# Generated by FakeRAM 2.0
VERSION 5.7 ;
BUSBITCHARS "[]" ;
PROPERTYDEFINITIONS
  MACRO width INTEGER ;
  MACRO depth INTEGER ;
  MACRO banks INTEGER ;
END PROPERTYDEFINITIONS
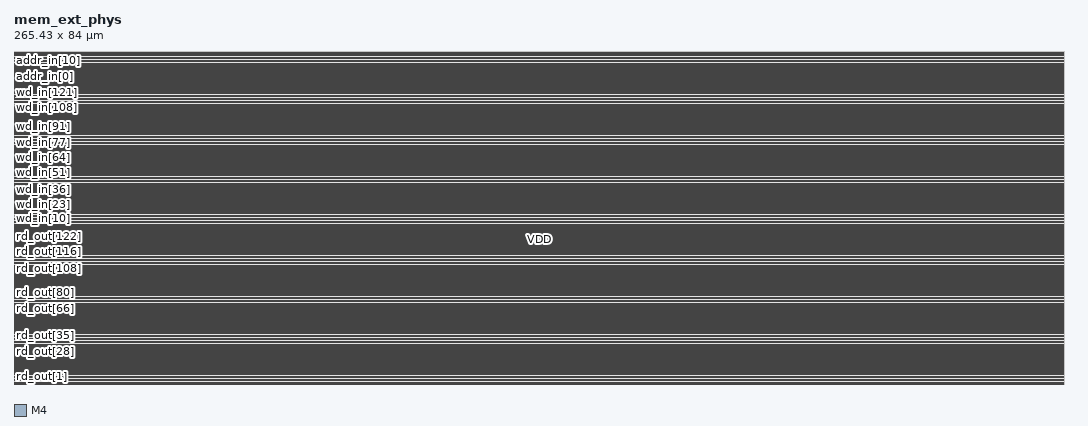
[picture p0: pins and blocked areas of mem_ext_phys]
MACRO mem_ext_phys
  PROPERTY width 128 ;
  PROPERTY depth 4096 ;
  PROPERTY banks 1 ;
  FOREIGN mem_ext 0 0 ;
  SYMMETRY X Y R90 ;
  SIZE 265.4300 BY 84.0000 ;
  CLASS BLOCK ;
  PIN rd_out[0]
    DIRECTION OUTPUT ;
    USE SIGNAL ;
    PORT
      LAYER M4 ;
      RECT 0.00000 0.04800 0.02400 0.07200 ;
    END
  END rd_out[0]
  PIN rd_out[1]
    DIRECTION OUTPUT ;
    USE SIGNAL ;
    PORT
      LAYER M4 ;
      RECT 0.00000 0.33600 0.02400 0.36000 ;
    END
  END rd_out[1]
  PIN rd_out[2]
    DIRECTION OUTPUT ;
    USE SIGNAL ;
    PORT
      LAYER M4 ;
      RECT 0.00000 0.62400 0.02400 0.64800 ;
    END
  END rd_out[2]
  PIN rd_out[3]
    DIRECTION OUTPUT ;
    USE SIGNAL ;
    PORT
      LAYER M4 ;
      RECT 0.00000 0.91200 0.02400 0.93600 ;
    END
  END rd_out[3]
  PIN rd_out[4]
    DIRECTION OUTPUT ;
    USE SIGNAL ;
    PORT
      LAYER M4 ;
      RECT 0.00000 1.20000 0.02400 1.22400 ;
    END
  END rd_out[4]
  PIN rd_out[5]
    DIRECTION OUTPUT ;
    USE SIGNAL ;
    PORT
      LAYER M4 ;
      RECT 0.00000 1.48800 0.02400 1.51200 ;
    END
  END rd_out[5]
  PIN rd_out[6]
    DIRECTION OUTPUT ;
    USE SIGNAL ;
    PORT
      LAYER M4 ;
      RECT 0.00000 1.77600 0.02400 1.80000 ;
    END
  END rd_out[6]
  PIN rd_out[7]
    DIRECTION OUTPUT ;
    USE SIGNAL ;
    PORT
      LAYER M4 ;
      RECT 0.00000 2.06400 0.02400 2.08800 ;
    END
  END rd_out[7]
  PIN rd_out[8]
    DIRECTION OUTPUT ;
    USE SIGNAL ;
    PORT
      LAYER M4 ;
      RECT 0.00000 2.35200 0.02400 2.37600 ;
    END
  END rd_out[8]
  PIN rd_out[9]
    DIRECTION OUTPUT ;
    USE SIGNAL ;
    PORT
      LAYER M4 ;
      RECT 0.00000 2.64000 0.02400 2.66400 ;
    END
  END rd_out[9]
  PIN rd_out[10]
    DIRECTION OUTPUT ;
    USE SIGNAL ;
    PORT
      LAYER M4 ;
      RECT 0.00000 2.92800 0.02400 2.95200 ;
    END
  END rd_out[10]
  PIN rd_out[11]
    DIRECTION OUTPUT ;
    USE SIGNAL ;
    PORT
      LAYER M4 ;
      RECT 0.00000 3.21600 0.02400 3.24000 ;
    END
  END rd_out[11]
  PIN rd_out[12]
    DIRECTION OUTPUT ;
    USE SIGNAL ;
    PORT
      LAYER M4 ;
      RECT 0.00000 3.50400 0.02400 3.52800 ;
    END
  END rd_out[12]
  PIN rd_out[13]
    DIRECTION OUTPUT ;
    USE SIGNAL ;
    PORT
      LAYER M4 ;
      RECT 0.00000 3.79200 0.02400 3.81600 ;
    END
  END rd_out[13]
  PIN rd_out[14]
    DIRECTION OUTPUT ;
    USE SIGNAL ;
    PORT
      LAYER M4 ;
      RECT 0.00000 4.08000 0.02400 4.10400 ;
    END
  END rd_out[14]
  PIN rd_out[15]
    DIRECTION OUTPUT ;
    USE SIGNAL ;
    PORT
      LAYER M4 ;
      RECT 0.00000 4.36800 0.02400 4.39200 ;
    END
  END rd_out[15]
  PIN rd_out[16]
    DIRECTION OUTPUT ;
    USE SIGNAL ;
    PORT
      LAYER M4 ;
      RECT 0.00000 4.65600 0.02400 4.68000 ;
    END
  END rd_out[16]
  PIN rd_out[17]
    DIRECTION OUTPUT ;
    USE SIGNAL ;
    PORT
      LAYER M4 ;
      RECT 0.00000 4.94400 0.02400 4.96800 ;
    END
  END rd_out[17]
  PIN rd_out[18]
    DIRECTION OUTPUT ;
    USE SIGNAL ;
    PORT
      LAYER M4 ;
      RECT 0.00000 5.23200 0.02400 5.25600 ;
    END
  END rd_out[18]
  PIN rd_out[19]
    DIRECTION OUTPUT ;
    USE SIGNAL ;
    PORT
      LAYER M4 ;
      RECT 0.00000 5.52000 0.02400 5.54400 ;
    END
  END rd_out[19]
  PIN rd_out[20]
    DIRECTION OUTPUT ;
    USE SIGNAL ;
    PORT
      LAYER M4 ;
      RECT 0.00000 5.80800 0.02400 5.83200 ;
    END
  END rd_out[20]
  PIN rd_out[21]
    DIRECTION OUTPUT ;
    USE SIGNAL ;
    PORT
      LAYER M4 ;
      RECT 0.00000 6.09600 0.02400 6.12000 ;
    END
  END rd_out[21]
  PIN rd_out[22]
    DIRECTION OUTPUT ;
    USE SIGNAL ;
    PORT
      LAYER M4 ;
      RECT 0.00000 6.38400 0.02400 6.40800 ;
    END
  END rd_out[22]
  PIN rd_out[23]
    DIRECTION OUTPUT ;
    USE SIGNAL ;
    PORT
      LAYER M4 ;
      RECT 0.00000 6.67200 0.02400 6.69600 ;
    END
  END rd_out[23]
  PIN rd_out[24]
    DIRECTION OUTPUT ;
    USE SIGNAL ;
    PORT
      LAYER M4 ;
      RECT 0.00000 6.96000 0.02400 6.98400 ;
    END
  END rd_out[24]
  PIN rd_out[25]
    DIRECTION OUTPUT ;
    USE SIGNAL ;
    PORT
      LAYER M4 ;
      RECT 0.00000 7.24800 0.02400 7.27200 ;
    END
  END rd_out[25]
  PIN rd_out[26]
    DIRECTION OUTPUT ;
    USE SIGNAL ;
    PORT
      LAYER M4 ;
      RECT 0.00000 7.53600 0.02400 7.56000 ;
    END
  END rd_out[26]
  PIN rd_out[27]
    DIRECTION OUTPUT ;
    USE SIGNAL ;
    PORT
      LAYER M4 ;
      RECT 0.00000 7.82400 0.02400 7.84800 ;
    END
  END rd_out[27]
  PIN rd_out[28]
    DIRECTION OUTPUT ;
    USE SIGNAL ;
    PORT
      LAYER M4 ;
      RECT 0.00000 8.11200 0.02400 8.13600 ;
    END
  END rd_out[28]
  PIN rd_out[29]
    DIRECTION OUTPUT ;
    USE SIGNAL ;
    PORT
      LAYER M4 ;
      RECT 0.00000 8.40000 0.02400 8.42400 ;
    END
  END rd_out[29]
  PIN rd_out[30]
    DIRECTION OUTPUT ;
    USE SIGNAL ;
    PORT
      LAYER M4 ;
      RECT 0.00000 8.68800 0.02400 8.71200 ;
    END
  END rd_out[30]
  PIN rd_out[31]
    DIRECTION OUTPUT ;
    USE SIGNAL ;
    PORT
      LAYER M4 ;
      RECT 0.00000 8.97600 0.02400 9.00000 ;
    END
  END rd_out[31]
  PIN rd_out[32]
    DIRECTION OUTPUT ;
    USE SIGNAL ;
    PORT
      LAYER M4 ;
      RECT 0.00000 9.26400 0.02400 9.28800 ;
    END
  END rd_out[32]
  PIN rd_out[33]
    DIRECTION OUTPUT ;
    USE SIGNAL ;
    PORT
      LAYER M4 ;
      RECT 0.00000 9.55200 0.02400 9.57600 ;
    END
  END rd_out[33]
  PIN rd_out[34]
    DIRECTION OUTPUT ;
    USE SIGNAL ;
    PORT
      LAYER M4 ;
      RECT 0.00000 9.84000 0.02400 9.86400 ;
    END
  END rd_out[34]
  PIN rd_out[35]
    DIRECTION OUTPUT ;
    USE SIGNAL ;
    PORT
      LAYER M4 ;
      RECT 0.00000 10.12800 0.02400 10.15200 ;
    END
  END rd_out[35]
  PIN rd_out[36]
    DIRECTION OUTPUT ;
    USE SIGNAL ;
    PORT
      LAYER M4 ;
      RECT 0.00000 10.41600 0.02400 10.44000 ;
    END
  END rd_out[36]
  PIN rd_out[37]
    DIRECTION OUTPUT ;
    USE SIGNAL ;
    PORT
      LAYER M4 ;
      RECT 0.00000 10.70400 0.02400 10.72800 ;
    END
  END rd_out[37]
  PIN rd_out[38]
    DIRECTION OUTPUT ;
    USE SIGNAL ;
    PORT
      LAYER M4 ;
      RECT 0.00000 10.99200 0.02400 11.01600 ;
    END
  END rd_out[38]
  PIN rd_out[39]
    DIRECTION OUTPUT ;
    USE SIGNAL ;
    PORT
      LAYER M4 ;
      RECT 0.00000 11.28000 0.02400 11.30400 ;
    END
  END rd_out[39]
  PIN rd_out[40]
    DIRECTION OUTPUT ;
    USE SIGNAL ;
    PORT
      LAYER M4 ;
      RECT 0.00000 11.56800 0.02400 11.59200 ;
    END
  END rd_out[40]
  PIN rd_out[41]
    DIRECTION OUTPUT ;
    USE SIGNAL ;
    PORT
      LAYER M4 ;
      RECT 0.00000 11.85600 0.02400 11.88000 ;
    END
  END rd_out[41]
  PIN rd_out[42]
    DIRECTION OUTPUT ;
    USE SIGNAL ;
    PORT
      LAYER M4 ;
      RECT 0.00000 12.14400 0.02400 12.16800 ;
    END
  END rd_out[42]
  PIN rd_out[43]
    DIRECTION OUTPUT ;
    USE SIGNAL ;
    PORT
      LAYER M4 ;
      RECT 0.00000 12.43200 0.02400 12.45600 ;
    END
  END rd_out[43]
  PIN rd_out[44]
    DIRECTION OUTPUT ;
    USE SIGNAL ;
    PORT
      LAYER M4 ;
      RECT 0.00000 12.72000 0.02400 12.74400 ;
    END
  END rd_out[44]
  PIN rd_out[45]
    DIRECTION OUTPUT ;
    USE SIGNAL ;
    PORT
      LAYER M4 ;
      RECT 0.00000 13.00800 0.02400 13.03200 ;
    END
  END rd_out[45]
  PIN rd_out[46]
    DIRECTION OUTPUT ;
    USE SIGNAL ;
    PORT
      LAYER M4 ;
      RECT 0.00000 13.29600 0.02400 13.32000 ;
    END
  END rd_out[46]
  PIN rd_out[47]
    DIRECTION OUTPUT ;
    USE SIGNAL ;
    PORT
      LAYER M4 ;
      RECT 0.00000 13.58400 0.02400 13.60800 ;
    END
  END rd_out[47]
  PIN rd_out[48]
    DIRECTION OUTPUT ;
    USE SIGNAL ;
    PORT
      LAYER M4 ;
      RECT 0.00000 13.87200 0.02400 13.89600 ;
    END
  END rd_out[48]
  PIN rd_out[49]
    DIRECTION OUTPUT ;
    USE SIGNAL ;
    PORT
      LAYER M4 ;
      RECT 0.00000 14.16000 0.02400 14.18400 ;
    END
  END rd_out[49]
  PIN rd_out[50]
    DIRECTION OUTPUT ;
    USE SIGNAL ;
    PORT
      LAYER M4 ;
      RECT 0.00000 14.44800 0.02400 14.47200 ;
    END
  END rd_out[50]
  PIN rd_out[51]
    DIRECTION OUTPUT ;
    USE SIGNAL ;
    PORT
      LAYER M4 ;
      RECT 0.00000 14.73600 0.02400 14.76000 ;
    END
  END rd_out[51]
  PIN rd_out[52]
    DIRECTION OUTPUT ;
    USE SIGNAL ;
    PORT
      LAYER M4 ;
      RECT 0.00000 15.02400 0.02400 15.04800 ;
    END
  END rd_out[52]
  PIN rd_out[53]
    DIRECTION OUTPUT ;
    USE SIGNAL ;
    PORT
      LAYER M4 ;
      RECT 0.00000 15.31200 0.02400 15.33600 ;
    END
  END rd_out[53]
  PIN rd_out[54]
    DIRECTION OUTPUT ;
    USE SIGNAL ;
    PORT
      LAYER M4 ;
      RECT 0.00000 15.60000 0.02400 15.62400 ;
    END
  END rd_out[54]
  PIN rd_out[55]
    DIRECTION OUTPUT ;
    USE SIGNAL ;
    PORT
      LAYER M4 ;
      RECT 0.00000 15.88800 0.02400 15.91200 ;
    END
  END rd_out[55]
  PIN rd_out[56]
    DIRECTION OUTPUT ;
    USE SIGNAL ;
    PORT
      LAYER M4 ;
      RECT 0.00000 16.17600 0.02400 16.20000 ;
    END
  END rd_out[56]
  PIN rd_out[57]
    DIRECTION OUTPUT ;
    USE SIGNAL ;
    PORT
      LAYER M4 ;
      RECT 0.00000 16.46400 0.02400 16.48800 ;
    END
  END rd_out[57]
  PIN rd_out[58]
    DIRECTION OUTPUT ;
    USE SIGNAL ;
    PORT
      LAYER M4 ;
      RECT 0.00000 16.75200 0.02400 16.77600 ;
    END
  END rd_out[58]
  PIN rd_out[59]
    DIRECTION OUTPUT ;
    USE SIGNAL ;
    PORT
      LAYER M4 ;
      RECT 0.00000 17.04000 0.02400 17.06400 ;
    END
  END rd_out[59]
  PIN rd_out[60]
    DIRECTION OUTPUT ;
    USE SIGNAL ;
    PORT
      LAYER M4 ;
      RECT 0.00000 17.32800 0.02400 17.35200 ;
    END
  END rd_out[60]
  PIN rd_out[61]
    DIRECTION OUTPUT ;
    USE SIGNAL ;
    PORT
      LAYER M4 ;
      RECT 0.00000 17.61600 0.02400 17.64000 ;
    END
  END rd_out[61]
  PIN rd_out[62]
    DIRECTION OUTPUT ;
    USE SIGNAL ;
    PORT
      LAYER M4 ;
      RECT 0.00000 17.90400 0.02400 17.92800 ;
    END
  END rd_out[62]
  PIN rd_out[63]
    DIRECTION OUTPUT ;
    USE SIGNAL ;
    PORT
      LAYER M4 ;
      RECT 0.00000 18.19200 0.02400 18.21600 ;
    END
  END rd_out[63]
  PIN rd_out[64]
    DIRECTION OUTPUT ;
    USE SIGNAL ;
    PORT
      LAYER M4 ;
      RECT 0.00000 18.48000 0.02400 18.50400 ;
    END
  END rd_out[64]
  PIN rd_out[65]
    DIRECTION OUTPUT ;
    USE SIGNAL ;
    PORT
      LAYER M4 ;
      RECT 0.00000 18.76800 0.02400 18.79200 ;
    END
  END rd_out[65]
  PIN rd_out[66]
    DIRECTION OUTPUT ;
    USE SIGNAL ;
    PORT
      LAYER M4 ;
      RECT 0.00000 19.05600 0.02400 19.08000 ;
    END
  END rd_out[66]
  PIN rd_out[67]
    DIRECTION OUTPUT ;
    USE SIGNAL ;
    PORT
      LAYER M4 ;
      RECT 0.00000 19.34400 0.02400 19.36800 ;
    END
  END rd_out[67]
  PIN rd_out[68]
    DIRECTION OUTPUT ;
    USE SIGNAL ;
    PORT
      LAYER M4 ;
      RECT 0.00000 19.63200 0.02400 19.65600 ;
    END
  END rd_out[68]
  PIN rd_out[69]
    DIRECTION OUTPUT ;
    USE SIGNAL ;
    PORT
      LAYER M4 ;
      RECT 0.00000 19.92000 0.02400 19.94400 ;
    END
  END rd_out[69]
  PIN rd_out[70]
    DIRECTION OUTPUT ;
    USE SIGNAL ;
    PORT
      LAYER M4 ;
      RECT 0.00000 20.20800 0.02400 20.23200 ;
    END
  END rd_out[70]
  PIN rd_out[71]
    DIRECTION OUTPUT ;
    USE SIGNAL ;
    PORT
      LAYER M4 ;
      RECT 0.00000 20.49600 0.02400 20.52000 ;
    END
  END rd_out[71]
  PIN rd_out[72]
    DIRECTION OUTPUT ;
    USE SIGNAL ;
    PORT
      LAYER M4 ;
      RECT 0.00000 20.78400 0.02400 20.80800 ;
    END
  END rd_out[72]
  PIN rd_out[73]
    DIRECTION OUTPUT ;
    USE SIGNAL ;
    PORT
      LAYER M4 ;
      RECT 0.00000 21.07200 0.02400 21.09600 ;
    END
  END rd_out[73]
  PIN rd_out[74]
    DIRECTION OUTPUT ;
    USE SIGNAL ;
    PORT
      LAYER M4 ;
      RECT 0.00000 21.36000 0.02400 21.38400 ;
    END
  END rd_out[74]
  PIN rd_out[75]
    DIRECTION OUTPUT ;
    USE SIGNAL ;
    PORT
      LAYER M4 ;
      RECT 0.00000 21.64800 0.02400 21.67200 ;
    END
  END rd_out[75]
  PIN rd_out[76]
    DIRECTION OUTPUT ;
    USE SIGNAL ;
    PORT
      LAYER M4 ;
      RECT 0.00000 21.93600 0.02400 21.96000 ;
    END
  END rd_out[76]
  PIN rd_out[77]
    DIRECTION OUTPUT ;
    USE SIGNAL ;
    PORT
      LAYER M4 ;
      RECT 0.00000 22.22400 0.02400 22.24800 ;
    END
  END rd_out[77]
  PIN rd_out[78]
    DIRECTION OUTPUT ;
    USE SIGNAL ;
    PORT
      LAYER M4 ;
      RECT 0.00000 22.51200 0.02400 22.53600 ;
    END
  END rd_out[78]
  PIN rd_out[79]
    DIRECTION OUTPUT ;
    USE SIGNAL ;
    PORT
      LAYER M4 ;
      RECT 0.00000 22.80000 0.02400 22.82400 ;
    END
  END rd_out[79]
  PIN rd_out[80]
    DIRECTION OUTPUT ;
    USE SIGNAL ;
    PORT
      LAYER M4 ;
      RECT 0.00000 23.08800 0.02400 23.11200 ;
    END
  END rd_out[80]
  PIN rd_out[81]
    DIRECTION OUTPUT ;
    USE SIGNAL ;
    PORT
      LAYER M4 ;
      RECT 0.00000 23.37600 0.02400 23.40000 ;
    END
  END rd_out[81]
  PIN rd_out[82]
    DIRECTION OUTPUT ;
    USE SIGNAL ;
    PORT
      LAYER M4 ;
      RECT 0.00000 23.66400 0.02400 23.68800 ;
    END
  END rd_out[82]
  PIN rd_out[83]
    DIRECTION OUTPUT ;
    USE SIGNAL ;
    PORT
      LAYER M4 ;
      RECT 0.00000 23.95200 0.02400 23.97600 ;
    END
  END rd_out[83]
  PIN rd_out[84]
    DIRECTION OUTPUT ;
    USE SIGNAL ;
    PORT
      LAYER M4 ;
      RECT 0.00000 24.24000 0.02400 24.26400 ;
    END
  END rd_out[84]
  PIN rd_out[85]
    DIRECTION OUTPUT ;
    USE SIGNAL ;
    PORT
      LAYER M4 ;
      RECT 0.00000 24.52800 0.02400 24.55200 ;
    END
  END rd_out[85]
  PIN rd_out[86]
    DIRECTION OUTPUT ;
    USE SIGNAL ;
    PORT
      LAYER M4 ;
      RECT 0.00000 24.81600 0.02400 24.84000 ;
    END
  END rd_out[86]
  PIN rd_out[87]
    DIRECTION OUTPUT ;
    USE SIGNAL ;
    PORT
      LAYER M4 ;
      RECT 0.00000 25.10400 0.02400 25.12800 ;
    END
  END rd_out[87]
  PIN rd_out[88]
    DIRECTION OUTPUT ;
    USE SIGNAL ;
    PORT
      LAYER M4 ;
      RECT 0.00000 25.39200 0.02400 25.41600 ;
    END
  END rd_out[88]
  PIN rd_out[89]
    DIRECTION OUTPUT ;
    USE SIGNAL ;
    PORT
      LAYER M4 ;
      RECT 0.00000 25.68000 0.02400 25.70400 ;
    END
  END rd_out[89]
  PIN rd_out[90]
    DIRECTION OUTPUT ;
    USE SIGNAL ;
    PORT
      LAYER M4 ;
      RECT 0.00000 25.96800 0.02400 25.99200 ;
    END
  END rd_out[90]
  PIN rd_out[91]
    DIRECTION OUTPUT ;
    USE SIGNAL ;
    PORT
      LAYER M4 ;
      RECT 0.00000 26.25600 0.02400 26.28000 ;
    END
  END rd_out[91]
  PIN rd_out[92]
    DIRECTION OUTPUT ;
    USE SIGNAL ;
    PORT
      LAYER M4 ;
      RECT 0.00000 26.54400 0.02400 26.56800 ;
    END
  END rd_out[92]
  PIN rd_out[93]
    DIRECTION OUTPUT ;
    USE SIGNAL ;
    PORT
      LAYER M4 ;
      RECT 0.00000 26.83200 0.02400 26.85600 ;
    END
  END rd_out[93]
  PIN rd_out[94]
    DIRECTION OUTPUT ;
    USE SIGNAL ;
    PORT
      LAYER M4 ;
      RECT 0.00000 27.12000 0.02400 27.14400 ;
    END
  END rd_out[94]
  PIN rd_out[95]
    DIRECTION OUTPUT ;
    USE SIGNAL ;
    PORT
      LAYER M4 ;
      RECT 0.00000 27.40800 0.02400 27.43200 ;
    END
  END rd_out[95]
  PIN rd_out[96]
    DIRECTION OUTPUT ;
    USE SIGNAL ;
    PORT
      LAYER M4 ;
      RECT 0.00000 27.69600 0.02400 27.72000 ;
    END
  END rd_out[96]
  PIN rd_out[97]
    DIRECTION OUTPUT ;
    USE SIGNAL ;
    PORT
      LAYER M4 ;
      RECT 0.00000 27.98400 0.02400 28.00800 ;
    END
  END rd_out[97]
  PIN rd_out[98]
    DIRECTION OUTPUT ;
    USE SIGNAL ;
    PORT
      LAYER M4 ;
      RECT 0.00000 28.27200 0.02400 28.29600 ;
    END
  END rd_out[98]
  PIN rd_out[99]
    DIRECTION OUTPUT ;
    USE SIGNAL ;
    PORT
      LAYER M4 ;
      RECT 0.00000 28.56000 0.02400 28.58400 ;
    END
  END rd_out[99]
  PIN rd_out[100]
    DIRECTION OUTPUT ;
    USE SIGNAL ;
    PORT
      LAYER M4 ;
      RECT 0.00000 28.84800 0.02400 28.87200 ;
    END
  END rd_out[100]
  PIN rd_out[101]
    DIRECTION OUTPUT ;
    USE SIGNAL ;
    PORT
      LAYER M4 ;
      RECT 0.00000 29.13600 0.02400 29.16000 ;
    END
  END rd_out[101]
  PIN rd_out[102]
    DIRECTION OUTPUT ;
    USE SIGNAL ;
    PORT
      LAYER M4 ;
      RECT 0.00000 29.42400 0.02400 29.44800 ;
    END
  END rd_out[102]
  PIN rd_out[103]
    DIRECTION OUTPUT ;
    USE SIGNAL ;
    PORT
      LAYER M4 ;
      RECT 0.00000 29.71200 0.02400 29.73600 ;
    END
  END rd_out[103]
  PIN rd_out[104]
    DIRECTION OUTPUT ;
    USE SIGNAL ;
    PORT
      LAYER M4 ;
      RECT 0.00000 30.00000 0.02400 30.02400 ;
    END
  END rd_out[104]
  PIN rd_out[105]
    DIRECTION OUTPUT ;
    USE SIGNAL ;
    PORT
      LAYER M4 ;
      RECT 0.00000 30.28800 0.02400 30.31200 ;
    END
  END rd_out[105]
  PIN rd_out[106]
    DIRECTION OUTPUT ;
    USE SIGNAL ;
    PORT
      LAYER M4 ;
      RECT 0.00000 30.57600 0.02400 30.60000 ;
    END
  END rd_out[106]
  PIN rd_out[107]
    DIRECTION OUTPUT ;
    USE SIGNAL ;
    PORT
      LAYER M4 ;
      RECT 0.00000 30.86400 0.02400 30.88800 ;
    END
  END rd_out[107]
  PIN rd_out[108]
    DIRECTION OUTPUT ;
    USE SIGNAL ;
    PORT
      LAYER M4 ;
      RECT 0.00000 31.15200 0.02400 31.17600 ;
    END
  END rd_out[108]
  PIN rd_out[109]
    DIRECTION OUTPUT ;
    USE SIGNAL ;
    PORT
      LAYER M4 ;
      RECT 0.00000 31.44000 0.02400 31.46400 ;
    END
  END rd_out[109]
  PIN rd_out[110]
    DIRECTION OUTPUT ;
    USE SIGNAL ;
    PORT
      LAYER M4 ;
      RECT 0.00000 31.72800 0.02400 31.75200 ;
    END
  END rd_out[110]
  PIN rd_out[111]
    DIRECTION OUTPUT ;
    USE SIGNAL ;
    PORT
      LAYER M4 ;
      RECT 0.00000 32.01600 0.02400 32.04000 ;
    END
  END rd_out[111]
  PIN rd_out[112]
    DIRECTION OUTPUT ;
    USE SIGNAL ;
    PORT
      LAYER M4 ;
      RECT 0.00000 32.30400 0.02400 32.32800 ;
    END
  END rd_out[112]
  PIN rd_out[113]
    DIRECTION OUTPUT ;
    USE SIGNAL ;
    PORT
      LAYER M4 ;
      RECT 0.00000 32.59200 0.02400 32.61600 ;
    END
  END rd_out[113]
  PIN rd_out[114]
    DIRECTION OUTPUT ;
    USE SIGNAL ;
    PORT
      LAYER M4 ;
      RECT 0.00000 32.88000 0.02400 32.90400 ;
    END
  END rd_out[114]
  PIN rd_out[115]
    DIRECTION OUTPUT ;
    USE SIGNAL ;
    PORT
      LAYER M4 ;
      RECT 0.00000 33.16800 0.02400 33.19200 ;
    END
  END rd_out[115]
  PIN rd_out[116]
    DIRECTION OUTPUT ;
    USE SIGNAL ;
    PORT
      LAYER M4 ;
      RECT 0.00000 33.45600 0.02400 33.48000 ;
    END
  END rd_out[116]
  PIN rd_out[117]
    DIRECTION OUTPUT ;
    USE SIGNAL ;
    PORT
      LAYER M4 ;
      RECT 0.00000 33.74400 0.02400 33.76800 ;
    END
  END rd_out[117]
  PIN rd_out[118]
    DIRECTION OUTPUT ;
    USE SIGNAL ;
    PORT
      LAYER M4 ;
      RECT 0.00000 34.03200 0.02400 34.05600 ;
    END
  END rd_out[118]
  PIN rd_out[119]
    DIRECTION OUTPUT ;
    USE SIGNAL ;
    PORT
      LAYER M4 ;
      RECT 0.00000 34.32000 0.02400 34.34400 ;
    END
  END rd_out[119]
  PIN rd_out[120]
    DIRECTION OUTPUT ;
    USE SIGNAL ;
    PORT
      LAYER M4 ;
      RECT 0.00000 34.60800 0.02400 34.63200 ;
    END
  END rd_out[120]
  PIN rd_out[121]
    DIRECTION OUTPUT ;
    USE SIGNAL ;
    PORT
      LAYER M4 ;
      RECT 0.00000 34.89600 0.02400 34.92000 ;
    END
  END rd_out[121]
  PIN rd_out[122]
    DIRECTION OUTPUT ;
    USE SIGNAL ;
    PORT
      LAYER M4 ;
      RECT 0.00000 35.18400 0.02400 35.20800 ;
    END
  END rd_out[122]
  PIN rd_out[123]
    DIRECTION OUTPUT ;
    USE SIGNAL ;
    PORT
      LAYER M4 ;
      RECT 0.00000 35.47200 0.02400 35.49600 ;
    END
  END rd_out[123]
  PIN rd_out[124]
    DIRECTION OUTPUT ;
    USE SIGNAL ;
    PORT
      LAYER M4 ;
      RECT 0.00000 35.76000 0.02400 35.78400 ;
    END
  END rd_out[124]
  PIN rd_out[125]
    DIRECTION OUTPUT ;
    USE SIGNAL ;
    PORT
      LAYER M4 ;
      RECT 0.00000 36.04800 0.02400 36.07200 ;
    END
  END rd_out[125]
  PIN rd_out[126]
    DIRECTION OUTPUT ;
    USE SIGNAL ;
    PORT
      LAYER M4 ;
      RECT 0.00000 36.33600 0.02400 36.36000 ;
    END
  END rd_out[126]
  PIN rd_out[127]
    DIRECTION OUTPUT ;
    USE SIGNAL ;
    PORT
      LAYER M4 ;
      RECT 0.00000 36.62400 0.02400 36.64800 ;
    END
  END rd_out[127]
  PIN wd_in[0]
    DIRECTION INPUT ;
    USE SIGNAL ;
    PORT
      LAYER M4 ;
      RECT 0.00000 38.83200 0.02400 38.85600 ;
    END
  END wd_in[0]
  PIN wd_in[1]
    DIRECTION INPUT ;
    USE SIGNAL ;
    PORT
      LAYER M4 ;
      RECT 0.00000 39.12000 0.02400 39.14400 ;
    END
  END wd_in[1]
  PIN wd_in[2]
    DIRECTION INPUT ;
    USE SIGNAL ;
    PORT
      LAYER M4 ;
      RECT 0.00000 39.40800 0.02400 39.43200 ;
    END
  END wd_in[2]
  PIN wd_in[3]
    DIRECTION INPUT ;
    USE SIGNAL ;
    PORT
      LAYER M4 ;
      RECT 0.00000 39.69600 0.02400 39.72000 ;
    END
  END wd_in[3]
  PIN wd_in[4]
    DIRECTION INPUT ;
    USE SIGNAL ;
    PORT
      LAYER M4 ;
      RECT 0.00000 39.98400 0.02400 40.00800 ;
    END
  END wd_in[4]
  PIN wd_in[5]
    DIRECTION INPUT ;
    USE SIGNAL ;
    PORT
      LAYER M4 ;
      RECT 0.00000 40.27200 0.02400 40.29600 ;
    END
  END wd_in[5]
  PIN wd_in[6]
    DIRECTION INPUT ;
    USE SIGNAL ;
    PORT
      LAYER M4 ;
      RECT 0.00000 40.56000 0.02400 40.58400 ;
    END
  END wd_in[6]
  PIN wd_in[7]
    DIRECTION INPUT ;
    USE SIGNAL ;
    PORT
      LAYER M4 ;
      RECT 0.00000 40.84800 0.02400 40.87200 ;
    END
  END wd_in[7]
  PIN wd_in[8]
    DIRECTION INPUT ;
    USE SIGNAL ;
    PORT
      LAYER M4 ;
      RECT 0.00000 41.13600 0.02400 41.16000 ;
    END
  END wd_in[8]
  PIN wd_in[9]
    DIRECTION INPUT ;
    USE SIGNAL ;
    PORT
      LAYER M4 ;
      RECT 0.00000 41.42400 0.02400 41.44800 ;
    END
  END wd_in[9]
  PIN wd_in[10]
    DIRECTION INPUT ;
    USE SIGNAL ;
    PORT
      LAYER M4 ;
      RECT 0.00000 41.71200 0.02400 41.73600 ;
    END
  END wd_in[10]
  PIN wd_in[11]
    DIRECTION INPUT ;
    USE SIGNAL ;
    PORT
      LAYER M4 ;
      RECT 0.00000 42.00000 0.02400 42.02400 ;
    END
  END wd_in[11]
  PIN wd_in[12]
    DIRECTION INPUT ;
    USE SIGNAL ;
    PORT
      LAYER M4 ;
      RECT 0.00000 42.28800 0.02400 42.31200 ;
    END
  END wd_in[12]
  PIN wd_in[13]
    DIRECTION INPUT ;
    USE SIGNAL ;
    PORT
      LAYER M4 ;
      RECT 0.00000 42.57600 0.02400 42.60000 ;
    END
  END wd_in[13]
  PIN wd_in[14]
    DIRECTION INPUT ;
    USE SIGNAL ;
    PORT
      LAYER M4 ;
      RECT 0.00000 42.86400 0.02400 42.88800 ;
    END
  END wd_in[14]
  PIN wd_in[15]
    DIRECTION INPUT ;
    USE SIGNAL ;
    PORT
      LAYER M4 ;
      RECT 0.00000 43.15200 0.02400 43.17600 ;
    END
  END wd_in[15]
  PIN wd_in[16]
    DIRECTION INPUT ;
    USE SIGNAL ;
    PORT
      LAYER M4 ;
      RECT 0.00000 43.44000 0.02400 43.46400 ;
    END
  END wd_in[16]
  PIN wd_in[17]
    DIRECTION INPUT ;
    USE SIGNAL ;
    PORT
      LAYER M4 ;
      RECT 0.00000 43.72800 0.02400 43.75200 ;
    END
  END wd_in[17]
  PIN wd_in[18]
    DIRECTION INPUT ;
    USE SIGNAL ;
    PORT
      LAYER M4 ;
      RECT 0.00000 44.01600 0.02400 44.04000 ;
    END
  END wd_in[18]
  PIN wd_in[19]
    DIRECTION INPUT ;
    USE SIGNAL ;
    PORT
      LAYER M4 ;
      RECT 0.00000 44.30400 0.02400 44.32800 ;
    END
  END wd_in[19]
  PIN wd_in[20]
    DIRECTION INPUT ;
    USE SIGNAL ;
    PORT
      LAYER M4 ;
      RECT 0.00000 44.59200 0.02400 44.61600 ;
    END
  END wd_in[20]
  PIN wd_in[21]
    DIRECTION INPUT ;
    USE SIGNAL ;
    PORT
      LAYER M4 ;
      RECT 0.00000 44.88000 0.02400 44.90400 ;
    END
  END wd_in[21]
  PIN wd_in[22]
    DIRECTION INPUT ;
    USE SIGNAL ;
    PORT
      LAYER M4 ;
      RECT 0.00000 45.16800 0.02400 45.19200 ;
    END
  END wd_in[22]
  PIN wd_in[23]
    DIRECTION INPUT ;
    USE SIGNAL ;
    PORT
      LAYER M4 ;
      RECT 0.00000 45.45600 0.02400 45.48000 ;
    END
  END wd_in[23]
  PIN wd_in[24]
    DIRECTION INPUT ;
    USE SIGNAL ;
    PORT
      LAYER M4 ;
      RECT 0.00000 45.74400 0.02400 45.76800 ;
    END
  END wd_in[24]
  PIN wd_in[25]
    DIRECTION INPUT ;
    USE SIGNAL ;
    PORT
      LAYER M4 ;
      RECT 0.00000 46.03200 0.02400 46.05600 ;
    END
  END wd_in[25]
  PIN wd_in[26]
    DIRECTION INPUT ;
    USE SIGNAL ;
    PORT
      LAYER M4 ;
      RECT 0.00000 46.32000 0.02400 46.34400 ;
    END
  END wd_in[26]
  PIN wd_in[27]
    DIRECTION INPUT ;
    USE SIGNAL ;
    PORT
      LAYER M4 ;
      RECT 0.00000 46.60800 0.02400 46.63200 ;
    END
  END wd_in[27]
  PIN wd_in[28]
    DIRECTION INPUT ;
    USE SIGNAL ;
    PORT
      LAYER M4 ;
      RECT 0.00000 46.89600 0.02400 46.92000 ;
    END
  END wd_in[28]
  PIN wd_in[29]
    DIRECTION INPUT ;
    USE SIGNAL ;
    PORT
      LAYER M4 ;
      RECT 0.00000 47.18400 0.02400 47.20800 ;
    END
  END wd_in[29]
  PIN wd_in[30]
    DIRECTION INPUT ;
    USE SIGNAL ;
    PORT
      LAYER M4 ;
      RECT 0.00000 47.47200 0.02400 47.49600 ;
    END
  END wd_in[30]
  PIN wd_in[31]
    DIRECTION INPUT ;
    USE SIGNAL ;
    PORT
      LAYER M4 ;
      RECT 0.00000 47.76000 0.02400 47.78400 ;
    END
  END wd_in[31]
  PIN wd_in[32]
    DIRECTION INPUT ;
    USE SIGNAL ;
    PORT
      LAYER M4 ;
      RECT 0.00000 48.04800 0.02400 48.07200 ;
    END
  END wd_in[32]
  PIN wd_in[33]
    DIRECTION INPUT ;
    USE SIGNAL ;
    PORT
      LAYER M4 ;
      RECT 0.00000 48.33600 0.02400 48.36000 ;
    END
  END wd_in[33]
  PIN wd_in[34]
    DIRECTION INPUT ;
    USE SIGNAL ;
    PORT
      LAYER M4 ;
      RECT 0.00000 48.62400 0.02400 48.64800 ;
    END
  END wd_in[34]
  PIN wd_in[35]
    DIRECTION INPUT ;
    USE SIGNAL ;
    PORT
      LAYER M4 ;
      RECT 0.00000 48.91200 0.02400 48.93600 ;
    END
  END wd_in[35]
  PIN wd_in[36]
    DIRECTION INPUT ;
    USE SIGNAL ;
    PORT
      LAYER M4 ;
      RECT 0.00000 49.20000 0.02400 49.22400 ;
    END
  END wd_in[36]
  PIN wd_in[37]
    DIRECTION INPUT ;
    USE SIGNAL ;
    PORT
      LAYER M4 ;
      RECT 0.00000 49.48800 0.02400 49.51200 ;
    END
  END wd_in[37]
  PIN wd_in[38]
    DIRECTION INPUT ;
    USE SIGNAL ;
    PORT
      LAYER M4 ;
      RECT 0.00000 49.77600 0.02400 49.80000 ;
    END
  END wd_in[38]
  PIN wd_in[39]
    DIRECTION INPUT ;
    USE SIGNAL ;
    PORT
      LAYER M4 ;
      RECT 0.00000 50.06400 0.02400 50.08800 ;
    END
  END wd_in[39]
  PIN wd_in[40]
    DIRECTION INPUT ;
    USE SIGNAL ;
    PORT
      LAYER M4 ;
      RECT 0.00000 50.35200 0.02400 50.37600 ;
    END
  END wd_in[40]
  PIN wd_in[41]
    DIRECTION INPUT ;
    USE SIGNAL ;
    PORT
      LAYER M4 ;
      RECT 0.00000 50.64000 0.02400 50.66400 ;
    END
  END wd_in[41]
  PIN wd_in[42]
    DIRECTION INPUT ;
    USE SIGNAL ;
    PORT
      LAYER M4 ;
      RECT 0.00000 50.92800 0.02400 50.95200 ;
    END
  END wd_in[42]
  PIN wd_in[43]
    DIRECTION INPUT ;
    USE SIGNAL ;
    PORT
      LAYER M4 ;
      RECT 0.00000 51.21600 0.02400 51.24000 ;
    END
  END wd_in[43]
  PIN wd_in[44]
    DIRECTION INPUT ;
    USE SIGNAL ;
    PORT
      LAYER M4 ;
      RECT 0.00000 51.50400 0.02400 51.52800 ;
    END
  END wd_in[44]
  PIN wd_in[45]
    DIRECTION INPUT ;
    USE SIGNAL ;
    PORT
      LAYER M4 ;
      RECT 0.00000 51.79200 0.02400 51.81600 ;
    END
  END wd_in[45]
  PIN wd_in[46]
    DIRECTION INPUT ;
    USE SIGNAL ;
    PORT
      LAYER M4 ;
      RECT 0.00000 52.08000 0.02400 52.10400 ;
    END
  END wd_in[46]
  PIN wd_in[47]
    DIRECTION INPUT ;
    USE SIGNAL ;
    PORT
      LAYER M4 ;
      RECT 0.00000 52.36800 0.02400 52.39200 ;
    END
  END wd_in[47]
  PIN wd_in[48]
    DIRECTION INPUT ;
    USE SIGNAL ;
    PORT
      LAYER M4 ;
      RECT 0.00000 52.65600 0.02400 52.68000 ;
    END
  END wd_in[48]
  PIN wd_in[49]
    DIRECTION INPUT ;
    USE SIGNAL ;
    PORT
      LAYER M4 ;
      RECT 0.00000 52.94400 0.02400 52.96800 ;
    END
  END wd_in[49]
  PIN wd_in[50]
    DIRECTION INPUT ;
    USE SIGNAL ;
    PORT
      LAYER M4 ;
      RECT 0.00000 53.23200 0.02400 53.25600 ;
    END
  END wd_in[50]
  PIN wd_in[51]
    DIRECTION INPUT ;
    USE SIGNAL ;
    PORT
      LAYER M4 ;
      RECT 0.00000 53.52000 0.02400 53.54400 ;
    END
  END wd_in[51]
  PIN wd_in[52]
    DIRECTION INPUT ;
    USE SIGNAL ;
    PORT
      LAYER M4 ;
      RECT 0.00000 53.80800 0.02400 53.83200 ;
    END
  END wd_in[52]
  PIN wd_in[53]
    DIRECTION INPUT ;
    USE SIGNAL ;
    PORT
      LAYER M4 ;
      RECT 0.00000 54.09600 0.02400 54.12000 ;
    END
  END wd_in[53]
  PIN wd_in[54]
    DIRECTION INPUT ;
    USE SIGNAL ;
    PORT
      LAYER M4 ;
      RECT 0.00000 54.38400 0.02400 54.40800 ;
    END
  END wd_in[54]
  PIN wd_in[55]
    DIRECTION INPUT ;
    USE SIGNAL ;
    PORT
      LAYER M4 ;
      RECT 0.00000 54.67200 0.02400 54.69600 ;
    END
  END wd_in[55]
  PIN wd_in[56]
    DIRECTION INPUT ;
    USE SIGNAL ;
    PORT
      LAYER M4 ;
      RECT 0.00000 54.96000 0.02400 54.98400 ;
    END
  END wd_in[56]
  PIN wd_in[57]
    DIRECTION INPUT ;
    USE SIGNAL ;
    PORT
      LAYER M4 ;
      RECT 0.00000 55.24800 0.02400 55.27200 ;
    END
  END wd_in[57]
  PIN wd_in[58]
    DIRECTION INPUT ;
    USE SIGNAL ;
    PORT
      LAYER M4 ;
      RECT 0.00000 55.53600 0.02400 55.56000 ;
    END
  END wd_in[58]
  PIN wd_in[59]
    DIRECTION INPUT ;
    USE SIGNAL ;
    PORT
      LAYER M4 ;
      RECT 0.00000 55.82400 0.02400 55.84800 ;
    END
  END wd_in[59]
  PIN wd_in[60]
    DIRECTION INPUT ;
    USE SIGNAL ;
    PORT
      LAYER M4 ;
      RECT 0.00000 56.11200 0.02400 56.13600 ;
    END
  END wd_in[60]
  PIN wd_in[61]
    DIRECTION INPUT ;
    USE SIGNAL ;
    PORT
      LAYER M4 ;
      RECT 0.00000 56.40000 0.02400 56.42400 ;
    END
  END wd_in[61]
  PIN wd_in[62]
    DIRECTION INPUT ;
    USE SIGNAL ;
    PORT
      LAYER M4 ;
      RECT 0.00000 56.68800 0.02400 56.71200 ;
    END
  END wd_in[62]
  PIN wd_in[63]
    DIRECTION INPUT ;
    USE SIGNAL ;
    PORT
      LAYER M4 ;
      RECT 0.00000 56.97600 0.02400 57.00000 ;
    END
  END wd_in[63]
  PIN wd_in[64]
    DIRECTION INPUT ;
    USE SIGNAL ;
    PORT
      LAYER M4 ;
      RECT 0.00000 57.26400 0.02400 57.28800 ;
    END
  END wd_in[64]
  PIN wd_in[65]
    DIRECTION INPUT ;
    USE SIGNAL ;
    PORT
      LAYER M4 ;
      RECT 0.00000 57.55200 0.02400 57.57600 ;
    END
  END wd_in[65]
  PIN wd_in[66]
    DIRECTION INPUT ;
    USE SIGNAL ;
    PORT
      LAYER M4 ;
      RECT 0.00000 57.84000 0.02400 57.86400 ;
    END
  END wd_in[66]
  PIN wd_in[67]
    DIRECTION INPUT ;
    USE SIGNAL ;
    PORT
      LAYER M4 ;
      RECT 0.00000 58.12800 0.02400 58.15200 ;
    END
  END wd_in[67]
  PIN wd_in[68]
    DIRECTION INPUT ;
    USE SIGNAL ;
    PORT
      LAYER M4 ;
      RECT 0.00000 58.41600 0.02400 58.44000 ;
    END
  END wd_in[68]
  PIN wd_in[69]
    DIRECTION INPUT ;
    USE SIGNAL ;
    PORT
      LAYER M4 ;
      RECT 0.00000 58.70400 0.02400 58.72800 ;
    END
  END wd_in[69]
  PIN wd_in[70]
    DIRECTION INPUT ;
    USE SIGNAL ;
    PORT
      LAYER M4 ;
      RECT 0.00000 58.99200 0.02400 59.01600 ;
    END
  END wd_in[70]
  PIN wd_in[71]
    DIRECTION INPUT ;
    USE SIGNAL ;
    PORT
      LAYER M4 ;
      RECT 0.00000 59.28000 0.02400 59.30400 ;
    END
  END wd_in[71]
  PIN wd_in[72]
    DIRECTION INPUT ;
    USE SIGNAL ;
    PORT
      LAYER M4 ;
      RECT 0.00000 59.56800 0.02400 59.59200 ;
    END
  END wd_in[72]
  PIN wd_in[73]
    DIRECTION INPUT ;
    USE SIGNAL ;
    PORT
      LAYER M4 ;
      RECT 0.00000 59.85600 0.02400 59.88000 ;
    END
  END wd_in[73]
  PIN wd_in[74]
    DIRECTION INPUT ;
    USE SIGNAL ;
    PORT
      LAYER M4 ;
      RECT 0.00000 60.14400 0.02400 60.16800 ;
    END
  END wd_in[74]
  PIN wd_in[75]
    DIRECTION INPUT ;
    USE SIGNAL ;
    PORT
      LAYER M4 ;
      RECT 0.00000 60.43200 0.02400 60.45600 ;
    END
  END wd_in[75]
  PIN wd_in[76]
    DIRECTION INPUT ;
    USE SIGNAL ;
    PORT
      LAYER M4 ;
      RECT 0.00000 60.72000 0.02400 60.74400 ;
    END
  END wd_in[76]
  PIN wd_in[77]
    DIRECTION INPUT ;
    USE SIGNAL ;
    PORT
      LAYER M4 ;
      RECT 0.00000 61.00800 0.02400 61.03200 ;
    END
  END wd_in[77]
  PIN wd_in[78]
    DIRECTION INPUT ;
    USE SIGNAL ;
    PORT
      LAYER M4 ;
      RECT 0.00000 61.29600 0.02400 61.32000 ;
    END
  END wd_in[78]
  PIN wd_in[79]
    DIRECTION INPUT ;
    USE SIGNAL ;
    PORT
      LAYER M4 ;
      RECT 0.00000 61.58400 0.02400 61.60800 ;
    END
  END wd_in[79]
  PIN wd_in[80]
    DIRECTION INPUT ;
    USE SIGNAL ;
    PORT
      LAYER M4 ;
      RECT 0.00000 61.87200 0.02400 61.89600 ;
    END
  END wd_in[80]
  PIN wd_in[81]
    DIRECTION INPUT ;
    USE SIGNAL ;
    PORT
      LAYER M4 ;
      RECT 0.00000 62.16000 0.02400 62.18400 ;
    END
  END wd_in[81]
  PIN wd_in[82]
    DIRECTION INPUT ;
    USE SIGNAL ;
    PORT
      LAYER M4 ;
      RECT 0.00000 62.44800 0.02400 62.47200 ;
    END
  END wd_in[82]
  PIN wd_in[83]
    DIRECTION INPUT ;
    USE SIGNAL ;
    PORT
      LAYER M4 ;
      RECT 0.00000 62.73600 0.02400 62.76000 ;
    END
  END wd_in[83]
  PIN wd_in[84]
    DIRECTION INPUT ;
    USE SIGNAL ;
    PORT
      LAYER M4 ;
      RECT 0.00000 63.02400 0.02400 63.04800 ;
    END
  END wd_in[84]
  PIN wd_in[85]
    DIRECTION INPUT ;
    USE SIGNAL ;
    PORT
      LAYER M4 ;
      RECT 0.00000 63.31200 0.02400 63.33600 ;
    END
  END wd_in[85]
  PIN wd_in[86]
    DIRECTION INPUT ;
    USE SIGNAL ;
    PORT
      LAYER M4 ;
      RECT 0.00000 63.60000 0.02400 63.62400 ;
    END
  END wd_in[86]
  PIN wd_in[87]
    DIRECTION INPUT ;
    USE SIGNAL ;
    PORT
      LAYER M4 ;
      RECT 0.00000 63.88800 0.02400 63.91200 ;
    END
  END wd_in[87]
  PIN wd_in[88]
    DIRECTION INPUT ;
    USE SIGNAL ;
    PORT
      LAYER M4 ;
      RECT 0.00000 64.17600 0.02400 64.20000 ;
    END
  END wd_in[88]
  PIN wd_in[89]
    DIRECTION INPUT ;
    USE SIGNAL ;
    PORT
      LAYER M4 ;
      RECT 0.00000 64.46400 0.02400 64.48800 ;
    END
  END wd_in[89]
  PIN wd_in[90]
    DIRECTION INPUT ;
    USE SIGNAL ;
    PORT
      LAYER M4 ;
      RECT 0.00000 64.75200 0.02400 64.77600 ;
    END
  END wd_in[90]
  PIN wd_in[91]
    DIRECTION INPUT ;
    USE SIGNAL ;
    PORT
      LAYER M4 ;
      RECT 0.00000 65.04000 0.02400 65.06400 ;
    END
  END wd_in[91]
  PIN wd_in[92]
    DIRECTION INPUT ;
    USE SIGNAL ;
    PORT
      LAYER M4 ;
      RECT 0.00000 65.32800 0.02400 65.35200 ;
    END
  END wd_in[92]
  PIN wd_in[93]
    DIRECTION INPUT ;
    USE SIGNAL ;
    PORT
      LAYER M4 ;
      RECT 0.00000 65.61600 0.02400 65.64000 ;
    END
  END wd_in[93]
  PIN wd_in[94]
    DIRECTION INPUT ;
    USE SIGNAL ;
    PORT
      LAYER M4 ;
      RECT 0.00000 65.90400 0.02400 65.92800 ;
    END
  END wd_in[94]
  PIN wd_in[95]
    DIRECTION INPUT ;
    USE SIGNAL ;
    PORT
      LAYER M4 ;
      RECT 0.00000 66.19200 0.02400 66.21600 ;
    END
  END wd_in[95]
  PIN wd_in[96]
    DIRECTION INPUT ;
    USE SIGNAL ;
    PORT
      LAYER M4 ;
      RECT 0.00000 66.48000 0.02400 66.50400 ;
    END
  END wd_in[96]
  PIN wd_in[97]
    DIRECTION INPUT ;
    USE SIGNAL ;
    PORT
      LAYER M4 ;
      RECT 0.00000 66.76800 0.02400 66.79200 ;
    END
  END wd_in[97]
  PIN wd_in[98]
    DIRECTION INPUT ;
    USE SIGNAL ;
    PORT
      LAYER M4 ;
      RECT 0.00000 67.05600 0.02400 67.08000 ;
    END
  END wd_in[98]
  PIN wd_in[99]
    DIRECTION INPUT ;
    USE SIGNAL ;
    PORT
      LAYER M4 ;
      RECT 0.00000 67.34400 0.02400 67.36800 ;
    END
  END wd_in[99]
  PIN wd_in[100]
    DIRECTION INPUT ;
    USE SIGNAL ;
    PORT
      LAYER M4 ;
      RECT 0.00000 67.63200 0.02400 67.65600 ;
    END
  END wd_in[100]
  PIN wd_in[101]
    DIRECTION INPUT ;
    USE SIGNAL ;
    PORT
      LAYER M4 ;
      RECT 0.00000 67.92000 0.02400 67.94400 ;
    END
  END wd_in[101]
  PIN wd_in[102]
    DIRECTION INPUT ;
    USE SIGNAL ;
    PORT
      LAYER M4 ;
      RECT 0.00000 68.20800 0.02400 68.23200 ;
    END
  END wd_in[102]
  PIN wd_in[103]
    DIRECTION INPUT ;
    USE SIGNAL ;
    PORT
      LAYER M4 ;
      RECT 0.00000 68.49600 0.02400 68.52000 ;
    END
  END wd_in[103]
  PIN wd_in[104]
    DIRECTION INPUT ;
    USE SIGNAL ;
    PORT
      LAYER M4 ;
      RECT 0.00000 68.78400 0.02400 68.80800 ;
    END
  END wd_in[104]
  PIN wd_in[105]
    DIRECTION INPUT ;
    USE SIGNAL ;
    PORT
      LAYER M4 ;
      RECT 0.00000 69.07200 0.02400 69.09600 ;
    END
  END wd_in[105]
  PIN wd_in[106]
    DIRECTION INPUT ;
    USE SIGNAL ;
    PORT
      LAYER M4 ;
      RECT 0.00000 69.36000 0.02400 69.38400 ;
    END
  END wd_in[106]
  PIN wd_in[107]
    DIRECTION INPUT ;
    USE SIGNAL ;
    PORT
      LAYER M4 ;
      RECT 0.00000 69.64800 0.02400 69.67200 ;
    END
  END wd_in[107]
  PIN wd_in[108]
    DIRECTION INPUT ;
    USE SIGNAL ;
    PORT
      LAYER M4 ;
      RECT 0.00000 69.93600 0.02400 69.96000 ;
    END
  END wd_in[108]
  PIN wd_in[109]
    DIRECTION INPUT ;
    USE SIGNAL ;
    PORT
      LAYER M4 ;
      RECT 0.00000 70.22400 0.02400 70.24800 ;
    END
  END wd_in[109]
  PIN wd_in[110]
    DIRECTION INPUT ;
    USE SIGNAL ;
    PORT
      LAYER M4 ;
      RECT 0.00000 70.51200 0.02400 70.53600 ;
    END
  END wd_in[110]
  PIN wd_in[111]
    DIRECTION INPUT ;
    USE SIGNAL ;
    PORT
      LAYER M4 ;
      RECT 0.00000 70.80000 0.02400 70.82400 ;
    END
  END wd_in[111]
  PIN wd_in[112]
    DIRECTION INPUT ;
    USE SIGNAL ;
    PORT
      LAYER M4 ;
      RECT 0.00000 71.08800 0.02400 71.11200 ;
    END
  END wd_in[112]
  PIN wd_in[113]
    DIRECTION INPUT ;
    USE SIGNAL ;
    PORT
      LAYER M4 ;
      RECT 0.00000 71.37600 0.02400 71.40000 ;
    END
  END wd_in[113]
  PIN wd_in[114]
    DIRECTION INPUT ;
    USE SIGNAL ;
    PORT
      LAYER M4 ;
      RECT 0.00000 71.66400 0.02400 71.68800 ;
    END
  END wd_in[114]
  PIN wd_in[115]
    DIRECTION INPUT ;
    USE SIGNAL ;
    PORT
      LAYER M4 ;
      RECT 0.00000 71.95200 0.02400 71.97600 ;
    END
  END wd_in[115]
  PIN wd_in[116]
    DIRECTION INPUT ;
    USE SIGNAL ;
    PORT
      LAYER M4 ;
      RECT 0.00000 72.24000 0.02400 72.26400 ;
    END
  END wd_in[116]
  PIN wd_in[117]
    DIRECTION INPUT ;
    USE SIGNAL ;
    PORT
      LAYER M4 ;
      RECT 0.00000 72.52800 0.02400 72.55200 ;
    END
  END wd_in[117]
  PIN wd_in[118]
    DIRECTION INPUT ;
    USE SIGNAL ;
    PORT
      LAYER M4 ;
      RECT 0.00000 72.81600 0.02400 72.84000 ;
    END
  END wd_in[118]
  PIN wd_in[119]
    DIRECTION INPUT ;
    USE SIGNAL ;
    PORT
      LAYER M4 ;
      RECT 0.00000 73.10400 0.02400 73.12800 ;
    END
  END wd_in[119]
  PIN wd_in[120]
    DIRECTION INPUT ;
    USE SIGNAL ;
    PORT
      LAYER M4 ;
      RECT 0.00000 73.39200 0.02400 73.41600 ;
    END
  END wd_in[120]
  PIN wd_in[121]
    DIRECTION INPUT ;
    USE SIGNAL ;
    PORT
      LAYER M4 ;
      RECT 0.00000 73.68000 0.02400 73.70400 ;
    END
  END wd_in[121]
  PIN wd_in[122]
    DIRECTION INPUT ;
    USE SIGNAL ;
    PORT
      LAYER M4 ;
      RECT 0.00000 73.96800 0.02400 73.99200 ;
    END
  END wd_in[122]
  PIN wd_in[123]
    DIRECTION INPUT ;
    USE SIGNAL ;
    PORT
      LAYER M4 ;
      RECT 0.00000 74.25600 0.02400 74.28000 ;
    END
  END wd_in[123]
  PIN wd_in[124]
    DIRECTION INPUT ;
    USE SIGNAL ;
    PORT
      LAYER M4 ;
      RECT 0.00000 74.54400 0.02400 74.56800 ;
    END
  END wd_in[124]
  PIN wd_in[125]
    DIRECTION INPUT ;
    USE SIGNAL ;
    PORT
      LAYER M4 ;
      RECT 0.00000 74.83200 0.02400 74.85600 ;
    END
  END wd_in[125]
  PIN wd_in[126]
    DIRECTION INPUT ;
    USE SIGNAL ;
    PORT
      LAYER M4 ;
      RECT 0.00000 75.12000 0.02400 75.14400 ;
    END
  END wd_in[126]
  PIN wd_in[127]
    DIRECTION INPUT ;
    USE SIGNAL ;
    PORT
      LAYER M4 ;
      RECT 0.00000 75.40800 0.02400 75.43200 ;
    END
  END wd_in[127]
  PIN addr_in[0]
    DIRECTION INPUT ;
    USE SIGNAL ;
    PORT
      LAYER M4 ;
      RECT 0.00000 77.61600 0.02400 77.64000 ;
    END
  END addr_in[0]
  PIN addr_in[1]
    DIRECTION INPUT ;
    USE SIGNAL ;
    PORT
      LAYER M4 ;
      RECT 0.00000 77.90400 0.02400 77.92800 ;
    END
  END addr_in[1]
  PIN addr_in[2]
    DIRECTION INPUT ;
    USE SIGNAL ;
    PORT
      LAYER M4 ;
      RECT 0.00000 78.19200 0.02400 78.21600 ;
    END
  END addr_in[2]
  PIN addr_in[3]
    DIRECTION INPUT ;
    USE SIGNAL ;
    PORT
      LAYER M4 ;
      RECT 0.00000 78.48000 0.02400 78.50400 ;
    END
  END addr_in[3]
  PIN addr_in[4]
    DIRECTION INPUT ;
    USE SIGNAL ;
    PORT
      LAYER M4 ;
      RECT 0.00000 78.76800 0.02400 78.79200 ;
    END
  END addr_in[4]
  PIN addr_in[5]
    DIRECTION INPUT ;
    USE SIGNAL ;
    PORT
      LAYER M4 ;
      RECT 0.00000 79.05600 0.02400 79.08000 ;
    END
  END addr_in[5]
  PIN addr_in[6]
    DIRECTION INPUT ;
    USE SIGNAL ;
    PORT
      LAYER M4 ;
      RECT 0.00000 79.34400 0.02400 79.36800 ;
    END
  END addr_in[6]
  PIN addr_in[7]
    DIRECTION INPUT ;
    USE SIGNAL ;
    PORT
      LAYER M4 ;
      RECT 0.00000 79.63200 0.02400 79.65600 ;
    END
  END addr_in[7]
  PIN addr_in[8]
    DIRECTION INPUT ;
    USE SIGNAL ;
    PORT
      LAYER M4 ;
      RECT 0.00000 79.92000 0.02400 79.94400 ;
    END
  END addr_in[8]
  PIN addr_in[9]
    DIRECTION INPUT ;
    USE SIGNAL ;
    PORT
      LAYER M4 ;
      RECT 0.00000 80.20800 0.02400 80.23200 ;
    END
  END addr_in[9]
  PIN addr_in[10]
    DIRECTION INPUT ;
    USE SIGNAL ;
    PORT
      LAYER M4 ;
      RECT 0.00000 80.49600 0.02400 80.52000 ;
    END
  END addr_in[10]
  PIN addr_in[11]
    DIRECTION INPUT ;
    USE SIGNAL ;
    PORT
      LAYER M4 ;
      RECT 0.00000 80.78400 0.02400 80.80800 ;
    END
  END addr_in[11]
  PIN we_in
    DIRECTION INPUT ;
    USE SIGNAL ;
    PORT
      LAYER M4 ;
      RECT 0.00000 82.99200 0.02400 83.01600 ;
    END
  END we_in
  PIN clk
    DIRECTION INPUT ;
    USE SIGNAL ;
    PORT
      LAYER M4 ;
      RECT 0.00000 83.28000 0.02400 83.30400 ;
    END
  END clk
  PIN ce_in
    DIRECTION INPUT ;
    USE SIGNAL ;
    PORT
      LAYER M4 ;
      RECT 0.00000 83.56800 0.02400 83.59200 ;
    END
  END ce_in
  PIN VDD
    DIRECTION INOUT ;
    USE POWER ;
    PORT
      LAYER M4 ;
      RECT 0.04800 0.38400 265.38200 0.48000 ;
      RECT 0.04800 1.15200 265.38200 1.24800 ;
      RECT 0.04800 1.92000 265.38200 2.01600 ;
      RECT 0.04800 2.68800 265.38200 2.78400 ;
      RECT 0.04800 3.45600 265.38200 3.55200 ;
      RECT 0.04800 4.22400 265.38200 4.32000 ;
      RECT 0.04800 4.99200 265.38200 5.08800 ;
      RECT 0.04800 5.76000 265.38200 5.85600 ;
      RECT 0.04800 6.52800 265.38200 6.62400 ;
      RECT 0.04800 7.29600 265.38200 7.39200 ;
      RECT 0.04800 8.06400 265.38200 8.16000 ;
      RECT 0.04800 8.83200 265.38200 8.92800 ;
      RECT 0.04800 9.60000 265.38200 9.69600 ;
      RECT 0.04800 10.36800 265.38200 10.46400 ;
      RECT 0.04800 11.13600 265.38200 11.23200 ;
      RECT 0.04800 11.90400 265.38200 12.00000 ;
      RECT 0.04800 12.67200 265.38200 12.76800 ;
      RECT 0.04800 13.44000 265.38200 13.53600 ;
      RECT 0.04800 14.20800 265.38200 14.30400 ;
      RECT 0.04800 14.97600 265.38200 15.07200 ;
      RECT 0.04800 15.74400 265.38200 15.84000 ;
      RECT 0.04800 16.51200 265.38200 16.60800 ;
      RECT 0.04800 17.28000 265.38200 17.37600 ;
      RECT 0.04800 18.04800 265.38200 18.14400 ;
      RECT 0.04800 18.81600 265.38200 18.91200 ;
      RECT 0.04800 19.58400 265.38200 19.68000 ;
      RECT 0.04800 20.35200 265.38200 20.44800 ;
      RECT 0.04800 21.12000 265.38200 21.21600 ;
      RECT 0.04800 21.88800 265.38200 21.98400 ;
      RECT 0.04800 22.65600 265.38200 22.75200 ;
      RECT 0.04800 23.42400 265.38200 23.52000 ;
      RECT 0.04800 24.19200 265.38200 24.28800 ;
      RECT 0.04800 24.96000 265.38200 25.05600 ;
      RECT 0.04800 25.72800 265.38200 25.82400 ;
      RECT 0.04800 26.49600 265.38200 26.59200 ;
      RECT 0.04800 27.26400 265.38200 27.36000 ;
      RECT 0.04800 28.03200 265.38200 28.12800 ;
      RECT 0.04800 28.80000 265.38200 28.89600 ;
      RECT 0.04800 29.56800 265.38200 29.66400 ;
      RECT 0.04800 30.33600 265.38200 30.43200 ;
      RECT 0.04800 31.10400 265.38200 31.20000 ;
      RECT 0.04800 31.87200 265.38200 31.96800 ;
      RECT 0.04800 32.64000 265.38200 32.73600 ;
      RECT 0.04800 33.40800 265.38200 33.50400 ;
      RECT 0.04800 34.17600 265.38200 34.27200 ;
      RECT 0.04800 34.94400 265.38200 35.04000 ;
      RECT 0.04800 35.71200 265.38200 35.80800 ;
      RECT 0.04800 36.48000 265.38200 36.57600 ;
      RECT 0.04800 37.24800 265.38200 37.34400 ;
      RECT 0.04800 38.01600 265.38200 38.11200 ;
      RECT 0.04800 38.78400 265.38200 38.88000 ;
      RECT 0.04800 39.55200 265.38200 39.64800 ;
      RECT 0.04800 40.32000 265.38200 40.41600 ;
      RECT 0.04800 41.08800 265.38200 41.18400 ;
      RECT 0.04800 41.85600 265.38200 41.95200 ;
      RECT 0.04800 42.62400 265.38200 42.72000 ;
      RECT 0.04800 43.39200 265.38200 43.48800 ;
      RECT 0.04800 44.16000 265.38200 44.25600 ;
      RECT 0.04800 44.92800 265.38200 45.02400 ;
      RECT 0.04800 45.69600 265.38200 45.79200 ;
      RECT 0.04800 46.46400 265.38200 46.56000 ;
      RECT 0.04800 47.23200 265.38200 47.32800 ;
      RECT 0.04800 48.00000 265.38200 48.09600 ;
      RECT 0.04800 48.76800 265.38200 48.86400 ;
      RECT 0.04800 49.53600 265.38200 49.63200 ;
      RECT 0.04800 50.30400 265.38200 50.40000 ;
      RECT 0.04800 51.07200 265.38200 51.16800 ;
      RECT 0.04800 51.84000 265.38200 51.93600 ;
      RECT 0.04800 52.60800 265.38200 52.70400 ;
      RECT 0.04800 53.37600 265.38200 53.47200 ;
      RECT 0.04800 54.14400 265.38200 54.24000 ;
      RECT 0.04800 54.91200 265.38200 55.00800 ;
      RECT 0.04800 55.68000 265.38200 55.77600 ;
      RECT 0.04800 56.44800 265.38200 56.54400 ;
      RECT 0.04800 57.21600 265.38200 57.31200 ;
      RECT 0.04800 57.98400 265.38200 58.08000 ;
      RECT 0.04800 58.75200 265.38200 58.84800 ;
      RECT 0.04800 59.52000 265.38200 59.61600 ;
      RECT 0.04800 60.28800 265.38200 60.38400 ;
      RECT 0.04800 61.05600 265.38200 61.15200 ;
      RECT 0.04800 61.82400 265.38200 61.92000 ;
      RECT 0.04800 62.59200 265.38200 62.68800 ;
      RECT 0.04800 63.36000 265.38200 63.45600 ;
      RECT 0.04800 64.12800 265.38200 64.22400 ;
      RECT 0.04800 64.89600 265.38200 64.99200 ;
      RECT 0.04800 65.66400 265.38200 65.76000 ;
      RECT 0.04800 66.43200 265.38200 66.52800 ;
      RECT 0.04800 67.20000 265.38200 67.29600 ;
      RECT 0.04800 67.96800 265.38200 68.06400 ;
      RECT 0.04800 68.73600 265.38200 68.83200 ;
      RECT 0.04800 69.50400 265.38200 69.60000 ;
      RECT 0.04800 70.27200 265.38200 70.36800 ;
      RECT 0.04800 71.04000 265.38200 71.13600 ;
      RECT 0.04800 71.80800 265.38200 71.90400 ;
      RECT 0.04800 72.57600 265.38200 72.67200 ;
      RECT 0.04800 73.34400 265.38200 73.44000 ;
      RECT 0.04800 74.11200 265.38200 74.20800 ;
      RECT 0.04800 74.88000 265.38200 74.97600 ;
      RECT 0.04800 75.64800 265.38200 75.74400 ;
      RECT 0.04800 76.41600 265.38200 76.51200 ;
      RECT 0.04800 77.18400 265.38200 77.28000 ;
      RECT 0.04800 77.95200 265.38200 78.04800 ;
      RECT 0.04800 78.72000 265.38200 78.81600 ;
      RECT 0.04800 79.48800 265.38200 79.58400 ;
      RECT 0.04800 80.25600 265.38200 80.35200 ;
      RECT 0.04800 81.02400 265.38200 81.12000 ;
      RECT 0.04800 81.79200 265.38200 81.88800 ;
      RECT 0.04800 82.56000 265.38200 82.65600 ;
      RECT 0.04800 83.32800 265.38200 83.42400 ;
    END
  END VDD
  PIN VSS
    DIRECTION INOUT ;
    USE GROUND ;
    PORT
      LAYER M4 ;
      RECT 0.04800 0.00000 265.38200 0.09600 ;
      RECT 0.04800 0.76800 265.38200 0.86400 ;
      RECT 0.04800 1.53600 265.38200 1.63200 ;
      RECT 0.04800 2.30400 265.38200 2.40000 ;
      RECT 0.04800 3.07200 265.38200 3.16800 ;
      RECT 0.04800 3.84000 265.38200 3.93600 ;
      RECT 0.04800 4.60800 265.38200 4.70400 ;
      RECT 0.04800 5.37600 265.38200 5.47200 ;
      RECT 0.04800 6.14400 265.38200 6.24000 ;
      RECT 0.04800 6.91200 265.38200 7.00800 ;
      RECT 0.04800 7.68000 265.38200 7.77600 ;
      RECT 0.04800 8.44800 265.38200 8.54400 ;
      RECT 0.04800 9.21600 265.38200 9.31200 ;
      RECT 0.04800 9.98400 265.38200 10.08000 ;
      RECT 0.04800 10.75200 265.38200 10.84800 ;
      RECT 0.04800 11.52000 265.38200 11.61600 ;
      RECT 0.04800 12.28800 265.38200 12.38400 ;
      RECT 0.04800 13.05600 265.38200 13.15200 ;
      RECT 0.04800 13.82400 265.38200 13.92000 ;
      RECT 0.04800 14.59200 265.38200 14.68800 ;
      RECT 0.04800 15.36000 265.38200 15.45600 ;
      RECT 0.04800 16.12800 265.38200 16.22400 ;
      RECT 0.04800 16.89600 265.38200 16.99200 ;
      RECT 0.04800 17.66400 265.38200 17.76000 ;
      RECT 0.04800 18.43200 265.38200 18.52800 ;
      RECT 0.04800 19.20000 265.38200 19.29600 ;
      RECT 0.04800 19.96800 265.38200 20.06400 ;
      RECT 0.04800 20.73600 265.38200 20.83200 ;
      RECT 0.04800 21.50400 265.38200 21.60000 ;
      RECT 0.04800 22.27200 265.38200 22.36800 ;
      RECT 0.04800 23.04000 265.38200 23.13600 ;
      RECT 0.04800 23.80800 265.38200 23.90400 ;
      RECT 0.04800 24.57600 265.38200 24.67200 ;
      RECT 0.04800 25.34400 265.38200 25.44000 ;
      RECT 0.04800 26.11200 265.38200 26.20800 ;
      RECT 0.04800 26.88000 265.38200 26.97600 ;
      RECT 0.04800 27.64800 265.38200 27.74400 ;
      RECT 0.04800 28.41600 265.38200 28.51200 ;
      RECT 0.04800 29.18400 265.38200 29.28000 ;
      RECT 0.04800 29.95200 265.38200 30.04800 ;
      RECT 0.04800 30.72000 265.38200 30.81600 ;
      RECT 0.04800 31.48800 265.38200 31.58400 ;
      RECT 0.04800 32.25600 265.38200 32.35200 ;
      RECT 0.04800 33.02400 265.38200 33.12000 ;
      RECT 0.04800 33.79200 265.38200 33.88800 ;
      RECT 0.04800 34.56000 265.38200 34.65600 ;
      RECT 0.04800 35.32800 265.38200 35.42400 ;
      RECT 0.04800 36.09600 265.38200 36.19200 ;
      RECT 0.04800 36.86400 265.38200 36.96000 ;
      RECT 0.04800 37.63200 265.38200 37.72800 ;
      RECT 0.04800 38.40000 265.38200 38.49600 ;
      RECT 0.04800 39.16800 265.38200 39.26400 ;
      RECT 0.04800 39.93600 265.38200 40.03200 ;
      RECT 0.04800 40.70400 265.38200 40.80000 ;
      RECT 0.04800 41.47200 265.38200 41.56800 ;
      RECT 0.04800 42.24000 265.38200 42.33600 ;
      RECT 0.04800 43.00800 265.38200 43.10400 ;
      RECT 0.04800 43.77600 265.38200 43.87200 ;
      RECT 0.04800 44.54400 265.38200 44.64000 ;
      RECT 0.04800 45.31200 265.38200 45.40800 ;
      RECT 0.04800 46.08000 265.38200 46.17600 ;
      RECT 0.04800 46.84800 265.38200 46.94400 ;
      RECT 0.04800 47.61600 265.38200 47.71200 ;
      RECT 0.04800 48.38400 265.38200 48.48000 ;
      RECT 0.04800 49.15200 265.38200 49.24800 ;
      RECT 0.04800 49.92000 265.38200 50.01600 ;
      RECT 0.04800 50.68800 265.38200 50.78400 ;
      RECT 0.04800 51.45600 265.38200 51.55200 ;
      RECT 0.04800 52.22400 265.38200 52.32000 ;
      RECT 0.04800 52.99200 265.38200 53.08800 ;
      RECT 0.04800 53.76000 265.38200 53.85600 ;
      RECT 0.04800 54.52800 265.38200 54.62400 ;
      RECT 0.04800 55.29600 265.38200 55.39200 ;
      RECT 0.04800 56.06400 265.38200 56.16000 ;
      RECT 0.04800 56.83200 265.38200 56.92800 ;
      RECT 0.04800 57.60000 265.38200 57.69600 ;
      RECT 0.04800 58.36800 265.38200 58.46400 ;
      RECT 0.04800 59.13600 265.38200 59.23200 ;
      RECT 0.04800 59.90400 265.38200 60.00000 ;
      RECT 0.04800 60.67200 265.38200 60.76800 ;
      RECT 0.04800 61.44000 265.38200 61.53600 ;
      RECT 0.04800 62.20800 265.38200 62.30400 ;
      RECT 0.04800 62.97600 265.38200 63.07200 ;
      RECT 0.04800 63.74400 265.38200 63.84000 ;
      RECT 0.04800 64.51200 265.38200 64.60800 ;
      RECT 0.04800 65.28000 265.38200 65.37600 ;
      RECT 0.04800 66.04800 265.38200 66.14400 ;
      RECT 0.04800 66.81600 265.38200 66.91200 ;
      RECT 0.04800 67.58400 265.38200 67.68000 ;
      RECT 0.04800 68.35200 265.38200 68.44800 ;
      RECT 0.04800 69.12000 265.38200 69.21600 ;
      RECT 0.04800 69.88800 265.38200 69.98400 ;
      RECT 0.04800 70.65600 265.38200 70.75200 ;
      RECT 0.04800 71.42400 265.38200 71.52000 ;
      RECT 0.04800 72.19200 265.38200 72.28800 ;
      RECT 0.04800 72.96000 265.38200 73.05600 ;
      RECT 0.04800 73.72800 265.38200 73.82400 ;
      RECT 0.04800 74.49600 265.38200 74.59200 ;
      RECT 0.04800 75.26400 265.38200 75.36000 ;
      RECT 0.04800 76.03200 265.38200 76.12800 ;
      RECT 0.04800 76.80000 265.38200 76.89600 ;
      RECT 0.04800 77.56800 265.38200 77.66400 ;
      RECT 0.04800 78.33600 265.38200 78.43200 ;
      RECT 0.04800 79.10400 265.38200 79.20000 ;
      RECT 0.04800 79.87200 265.38200 79.96800 ;
      RECT 0.04800 80.64000 265.38200 80.73600 ;
      RECT 0.04800 81.40800 265.38200 81.50400 ;
      RECT 0.04800 82.17600 265.38200 82.27200 ;
      RECT 0.04800 82.94400 265.38200 83.04000 ;
      RECT 0.04800 83.71200 265.38200 83.80800 ;
    END
  END VSS
  OBS
    LAYER M1 ;
    RECT 0 0 265.43000 84.00000 ;
    LAYER M2 ;
    RECT 0 0 265.43000 84.00000 ;
    LAYER M3 ;
    RECT 0 0 265.43000 84.00000 ;
    LAYER M4 ;
    RECT 0 0 265.43000 84.00000 ;
  END
END mem_ext_phys
END LIBRARY
